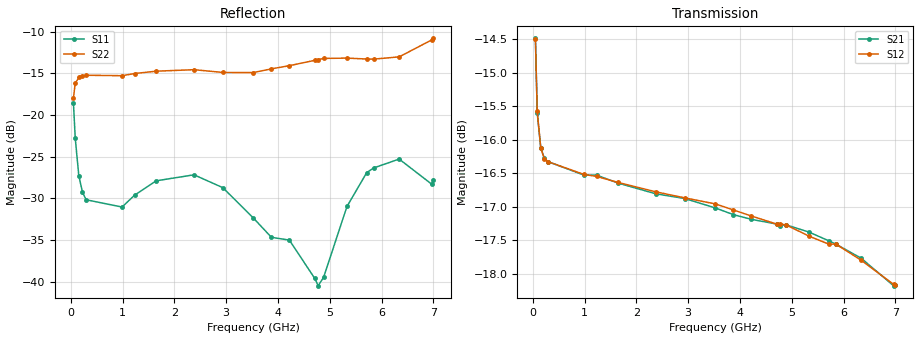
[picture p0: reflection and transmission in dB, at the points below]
! Integrated Device Technology
! Corporate Headquarters
! 6024 Silver Creek Valley Road
! San Jose, CA 95138  USA
! Phone:  1-408-284-8200
! Toll Free:  1-800-223-1366
! Webpage:  http://www.idt.com/
! Timing and RF Division
! 515 Groton Road, Suite 102
! Westford, MA 01886-6024
! Device:  F2258
! Description: Voltage Variable RF Attenuator
! Frequency:  50.0 -  6000.00 MHz
! Package:  3x3 mm Thin QFN Plastic Package: 16 pin
! Ports:  2 RF, 2 DC
!  Pin  1  = NC
!  Pin  2  = NC
!  Pin  3  = RF2  = Port 2
!  Pin  4  = GND
!  Pin  5  = Vdd
!  Pin  6  = NC
!  Pin  7  = VCTRL
!  Pin  8  = NC
!  Pin  9  = GND
!  Pin 10  = RF1  = Port 1
!  Pin 11  = NC
!  Pin 12  = NC
!  Pin 13  = NC
!  Pin 14  = NC
!  Pin 15  = NC
!  Pin 16  = NC
! Vcntrl:  1.220 Volts
! Vdd:  +3.300 Volts
! Current:  1.166 mA
! Data:  The device was measured on a the F2258 evaluation board which has
!  individual transmission lines to the RF pins.  Data was collected
!  using a calibrated network analyzer.  The evaluation board was
!  de-embedded using a TRL calibration technique.
!  The reference plane is the edge of the package pin.
! Misc:  SN 10
!  Action Tracker AT0285
! Date Measured:  2014-12-10
! Date:  2016-01-13  MJV
! Note:
!  Integrated Device Technology supplies this data as a sample of measured
!  data at the package pin for this product.  Your particular data for this
!  product may vary.
!  Data was taken at 25 degrees C.
!  Integrated Device Technology reserves the right to change this data at anytime.
!Freq_(GHz)  S11M_(dB)  S11P_(deg)  S21M_(dB)  S21P_(deg)  S12M_(dB)  S12P_(deg)  S22M_(dB)  S22P_(deg)
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# GHz S dB R 50
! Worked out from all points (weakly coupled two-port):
!   201 points, 50 MHz to 7 GHz, reference 50 ohm
!   highest |S21| = -14.49 dB at 50 MHz (marker M1); lowest = -18.2 dB at 6.965 GHz (marker M2)
!   lowest |S11| = -40.5 dB at 4.776 GHz (marker M3), VSWR 1.02, Z = 50.6 + j0.762 ohm
!   |S11| at or under -10 dB: start of sweep to end of sweep
!   |S22| runs from -18.0 to -10.8 dB; largest |S21 - S12| = 0.0012
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0.05  -18.56 -95.9  -14.49 -24.4  -14.50 -24.4  -17.97 -23.8
0.08475  -22.79 -82.9  -15.60 -17.4  -15.58 -17.4  -16.20 -12.3
0.15425  -27.33 -63.4  -16.13 -12.0  -16.13 -12.0  -15.50 -9.3
0.22375  -29.25 -50.2  -16.28 -10.2  -16.29 -10.3  -15.31 -9.3
0.29325  -30.18 -39.2  -16.33 -9.8  -16.33 -9.8  -15.24 -10.5
0.98825  -31.06 -19.4  -16.53 -16.6  -16.52 -16.6  -15.29 -27.9
1.2315  -29.63 -13.9  -16.53 -19.9  -16.55 -19.9  -15.03 -33.8
1.6485  -27.91 -8.4  -16.65 -25.6  -16.64 -25.6  -14.75 -43.5
2.37825  -27.19 4.9  -16.81 -35.7  -16.78 -35.7  -14.57 -60.4
2.93425  -28.73 20.4  -16.88 -43.6  -16.87 -43.6  -14.90 -76.2
3.525  -32.38 49.2  -17.02 -52.1  -16.96 -52.2  -14.91 -98.1
3.8725  -34.69 76.1  -17.12 -57.1  -17.05 -57.2  -14.47 -111.1
4.22  -35.03 90.9  -17.19 -62.1  -17.14 -62.2  -14.09 -121.2
4.7065  -39.60 65.2  -17.26 -69.0  -17.26 -69.0  -13.45 -131.4
4.776  -40.50 53.0  -17.29 -70.0  -17.26 -70.0  -13.35 -132.5
4.88025  -39.50 30.7  -17.27 -71.5  -17.27 -71.5  -13.22 -133.9
5.332  -30.99 -3.0  -17.38 -77.8  -17.44 -77.6  -13.18 -139.5
5.71425  -26.92 -2.4  -17.51 -83.0  -17.56 -82.8  -13.29 -145.2
5.85325  -26.35 0.2  -17.56 -84.9  -17.56 -84.9  -13.30 -148.4
6.33975  -25.30 12.8  -17.77 -91.7  -17.80 -91.6  -13.03 -160.5
6.96525  -28.30 79.0  -18.18 -99.2  -18.16 -99.2  -11.01 -179.2
7  -27.85 86.4  -18.17 -99.5  -18.17 -99.6  -10.81 179.8
